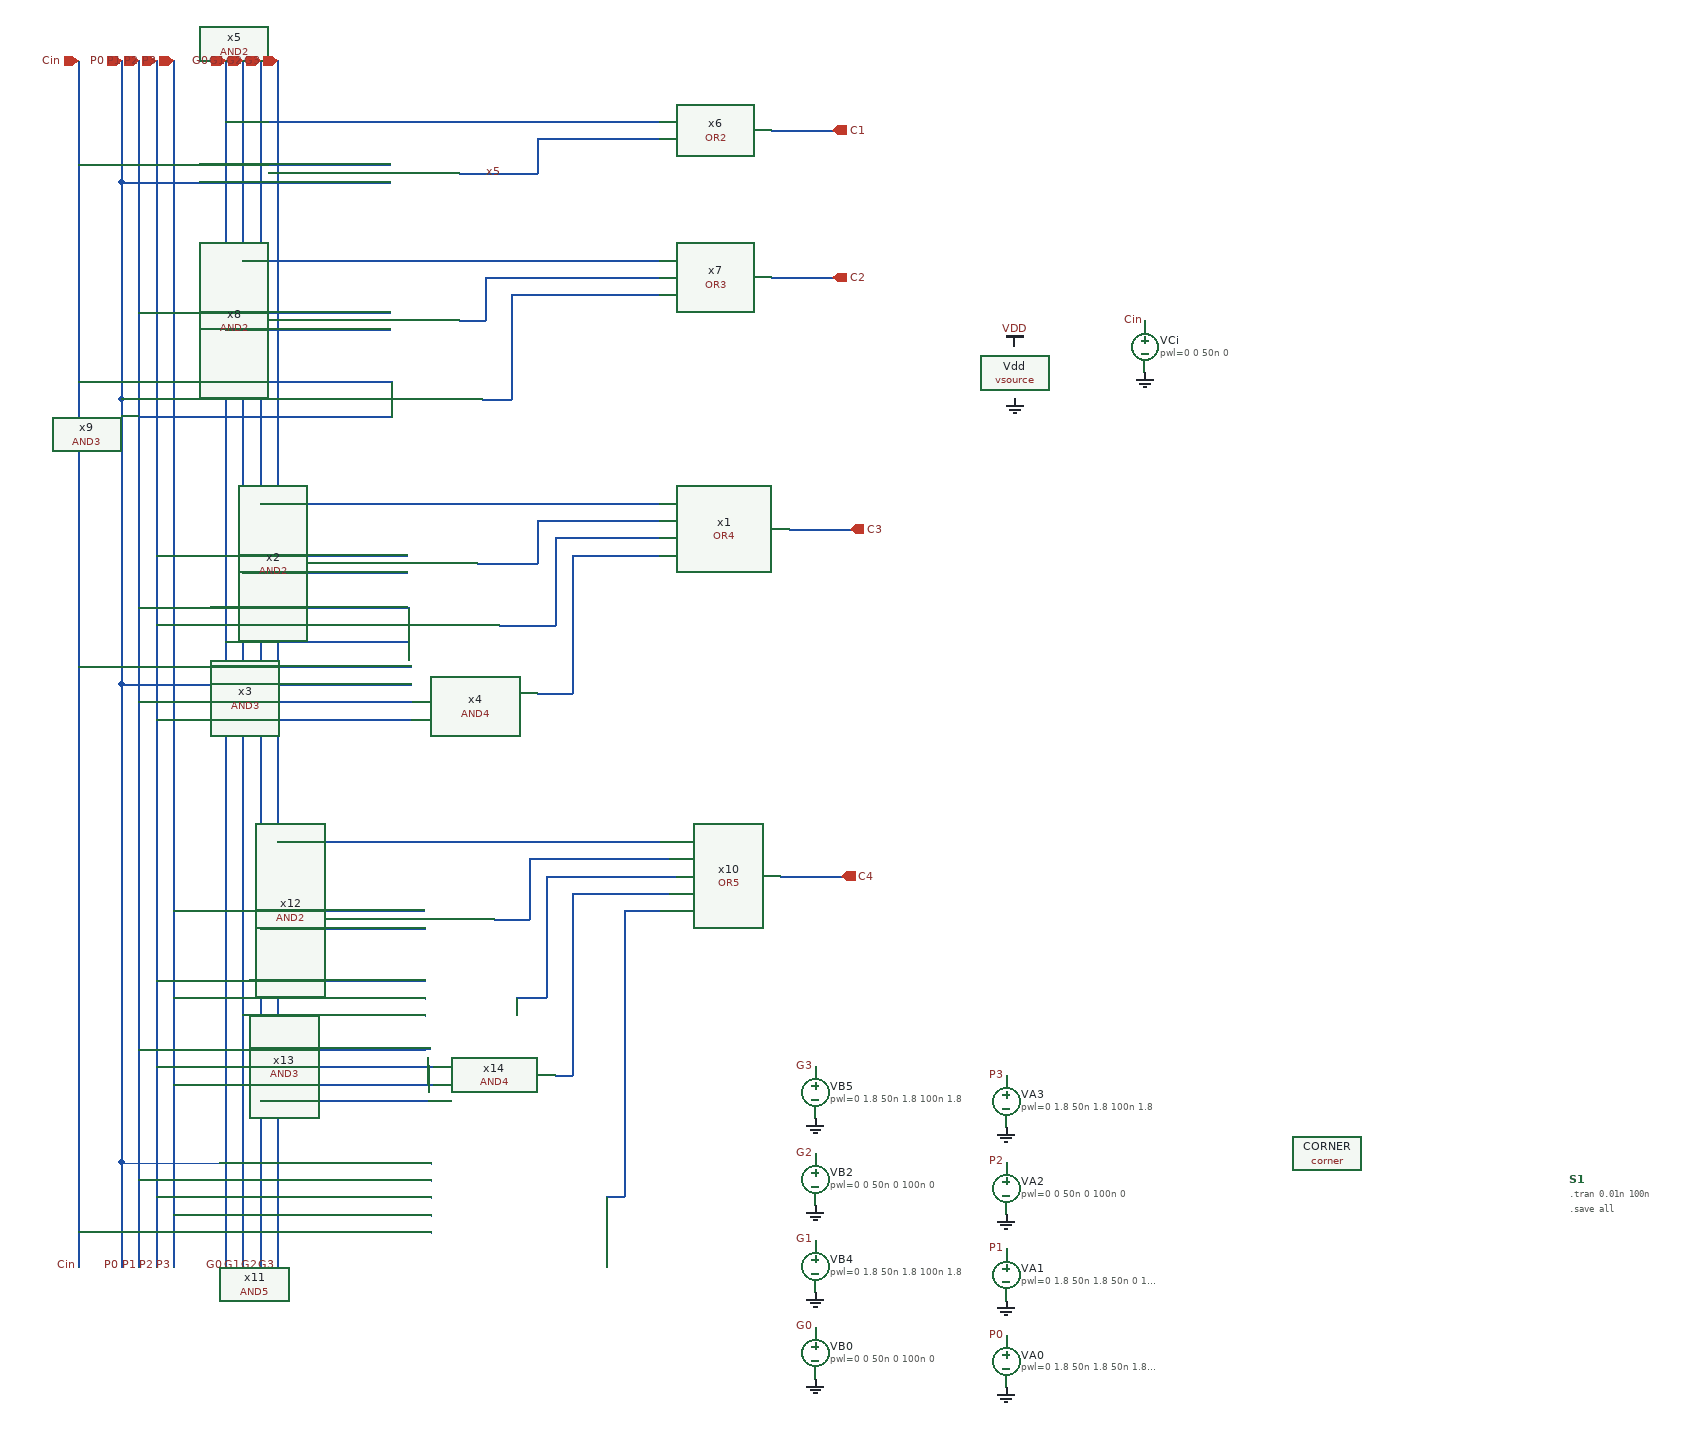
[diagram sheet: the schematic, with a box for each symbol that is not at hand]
v {xschem version=3.4.5 file_version=1.2
}
G {}
K {}
V {}
S {}
E {}
B 2 2080 -1280 2880 -880 {flags=graph
y1=0
y2=2
ypos1=-0.31094502
ypos2=1.6890548
divy=5
subdivy=1
unity=1
x1=0
x2=10e-8
divx=5
subdivx=1
xlabmag=1.0
ylabmag=1.0


dataset=-1
unitx=1
logx=0
logy=0
digital=1

color="8 8 11 6"
node="p;p3,p2,p1,p0
g;g3,g2,g1,g0
c;c4,c3,c2,c1
x5"}
N 1300 -1760 1610 -1760 {
lab=G0}
N 1050 -1710 1340 -1710 {
lab=Cin}
N 1100 -1690 1340 -1690 {
lab=P0}
N 1490 -1700 1500 -1700 {
lab=x5}
N 1580 -1740 1610 -1740 {
lab=x5}
N 1340 -1690 1410 -1690 {
lab=P0}
N 1340 -1710 1410 -1710 {
lab=Cin}
N 1320 -1600 1610 -1600 {
lab=G1}
N 1220 -1760 1300 -1760 {
lab=G0}
N 1500 -1700 1580 -1700 {
lab=x5}
N 1580 -1740 1580 -1700 {
lab=x5}
N 1240 -1600 1320 -1600 {
lab=G1}
N 1120 -1540 1410 -1540 {
lab=P1}
N 1220 -1520 1410 -1520 {
lab=G0}
N 1120 -1420 1410 -1420 {
lab=P1}
N 1100 -1440 1410 -1440 {
lab=P0}
N 1050 -1460 1410 -1460 {
lab=Cin}
N 1490 -1530 1520 -1530 {
lab=#net1}
N 1520 -1580 1520 -1530 {
lab=#net1}
N 1520 -1580 1610 -1580 {
lab=#net1}
N 1550 -1560 1550 -1440 {
lab=#net2}
N 1550 -1560 1610 -1560 {
lab=#net2}
N 1260 -1320 1610 -1320 {
lab=G2}
N 1610 -1760 1720 -1760 {
lab=G0}
N 1610 -1740 1720 -1740 {
lab=x5}
N 1610 -1600 1720 -1600 {
lab=G1}
N 1610 -1580 1720 -1580 {
lab=#net1}
N 1610 -1560 1720 -1560 {
lab=#net2}
N 1610 -1320 1720 -1320 {
lab=G2}
N 1050 -1131 1435 -1131 {
lab=Cin}
N 1101 -1111 1435 -1111 {
lab=P0}
N 1100 -1111 1101 -1111 {
lab=P0}
N 1120 -1091 1436 -1091 {
lab=P1}
N 1140 -1071 1435 -1071 {
lab=P2}
N 1220 -1160 1430 -1160 {
lab=G0}
N 1240 -1240 1430 -1240 {
lab=G1}
N 1120 -1200 1430 -1200 {
lab=P1}
N 1140 -1180 1430 -1180 {
lab=P2}
N 1140 -1260 1430 -1260 {
lab=P2}
N 1510 -1250 1580 -1250 {
lab=#net3}
N 1580 -1300 1580 -1250 {
lab=#net3}
N 1580 -1300 1720 -1300 {
lab=#net3}
N 1600 -1280 1600 -1180 {
lab=#net4}
N 1600 -1280 1720 -1280 {
lab=#net4}
N 1580 -1100 1620 -1100 {
lab=#net5}
N 1620 -1260 1620 -1100 {
lab=#net5}
N 1620 -1260 1720 -1260 {
lab=#net5}
N 1260 -830 1450 -830 {
lab=G2}
N 1160 -850 1449 -850 {
lab=P3}
N 1140 -770 1451 -769 {
lab=P2}
N 1160 -750 1451 -749 {
lab=P3}
N 1240 -730 1451 -729 {
lab=G1}
N 1160 -500 1457 -499 {
lab=P3}
N 1140 -520 1457 -519 {
lab=P2}
N 1120 -540 1457 -539 {
lab=P1}
N 1100 -560 1457 -559 {
lab=P0}
N 1050 -480 1457 -479 {
lab=Cin}
N 1530 -840 1570 -840 {
lab=#net6}
N 1570 -910 1570 -840 {
lab=#net6}
N 1570 -910 1730 -910 {
lab=#net6}
N 1560 -750 1590 -750 {
lab=#net7}
N 1590 -890 1590 -750 {
lab=#net7}
N 1590 -890 1740 -890 {
lab=#net7}
N 1600 -660 1620 -660 {
lab=#net8}
N 1620 -870 1620 -660 {
lab=#net8}
N 1620 -870 1730 -870 {
lab=#net8}
N 1660 -520 1680 -520 {
lab=#net9}
N 1680 -850 1680 -520 {
lab=#net9}
N 1850 -1750 1920 -1750 {
lab=C1}
N 1850 -1580 1920 -1580 {
lab=C2}
N 1870 -1290 1940 -1290 {
lab=C3}
N 1860 -890 1930 -890 {
lab=C4}
N 1280 -930 1722 -930 {
lab=G3}
N 1680 -850 1722 -850 {
lab=#net9}
N 1730 -870 1732 -870 {
lab=#net8}
N 1730 -910 1732 -910 {
lab=#net6}
N 1411 -1420 1411 -1419 {
lab=P1}
N 1410 -1420 1411 -1420 {
lab=P1}
N 1411 -1440 1411 -1439 {
lab=P0}
N 1410 -1440 1411 -1440 {
lab=P0}
N 1411 -1460 1411 -1459 {
lab=Cin}
N 1410 -1460 1411 -1460 {
lab=Cin}
N 1431 -1160 1431 -1159 {
lab=G0}
N 1430 -1160 1431 -1160 {
lab=G0}
N 1431 -1180 1431 -1179 {
lab=P2}
N 1430 -1180 1431 -1180 {
lab=P2}
N 1431 -1200 1431 -1199 {
lab=P1}
N 1429 -1200 1431 -1200 {
lab=P1}
N 1050 -1829 1050 -439 {
lab=Cin}
N 1120 -1830 1120 -440 {
lab=P1}
N 1140 -1830 1140 -440 {
lab=P2}
N 1160 -1830 1160 -440 {
lab=P3}
N 1220 -1830 1220 -440 {
lab=G0}
N 1240 -1830 1240 -440 {
lab=G1}
N 1260 -1830 1260 -440 {
lab=G2}
N 1280 -1830 1280 -440 {
lab=G3}
N 1240 -440 1240 -439 {
lab=G1}
N 1280 -440 1280 -439 {
lab=G3}
N 1260 -440 1260 -439 {
lab=G2}
N 1220 -440 1220 -439 {
lab=G0}
N 1160 -440 1160 -439 {
lab=P3}
N 1140 -440 1140 -439 {
lab=P2}
N 1120 -440 1120 -439 {
lab=P1}
N 1100 -440 1100 -439 {
lab=P0}
N 1100 -1830 1100 -1690 {
lab=P0}
N 1100 -1690 1100 -1440 {
lab=P0}
N 1100 -1440 1100 -1111 {
lab=P0}
N 1100 -1111 1100 -560 {
lab=P0}
N 1100 -560 1100 -439 {
lab=P0}
N 1516 -1439 1550 -1439 {
lab=#net2}
N 1550 -1440 1550 -1439 {
lab=#net2}
N 1536 -1179 1600 -1179 {
lab=#net4}
N 1600 -1180 1600 -1179 {
lab=#net4}
N 1556 -750 1556 -749 {
lab=#net7}
N 1556 -750 1560 -750 {
lab=#net7}
N 1659 -520 1659 -519 {
lab=#net9}
N 1659 -520 1660 -520 {
lab=#net9}
N 1120 -690 1450 -690 {
lab=P1}
N 1140 -670 1460 -670 {
lab=P2}
N 1160 -650 1460 -650 {
lab=P3}
N 1450 -691 1456 -691 {
lab=P1}
N 1450 -691 1450 -690 {
lab=P1}
N 1454 -671 1454 -670 {
lab=P2}
N 1454 -651 1454 -650 {
lab=P3}
N 1260 -631 1454 -631 {
lab=G2}
C {AND2.sym} 1450 -1700 0 0 {name=x5}
C {OR2.sym} 1770 -1750 0 0 {name=x6}
C {OR3.sym} 1790 -1580 0 0 {name=x7}
C {AND2.sym} 1450 -1530 0 0 {name=x8}
C {AND3.sym} 1460 -1440 0 0 {name=x9}
C {devices/ipin.sym} 1100 -1830 1 0 {name=p1 sig_type=std_logic lab=P0}
C {devices/ipin.sym} 1120 -1830 1 0 {name=p2 sig_type=std_logic lab=P1}
C {devices/ipin.sym} 1140 -1830 1 0 {name=p3 sig_type=std_logic lab=P2}
C {devices/ipin.sym} 1160 -1830 1 0 {name=p4 sig_type=std_logic lab=P3}
C {devices/ipin.sym} 1220 -1830 1 0 {name=p5 sig_type=std_logic lab=G0}
C {devices/ipin.sym} 1240 -1830 1 0 {name=p6 sig_type=std_logic lab=G1}
C {devices/ipin.sym} 1260 -1830 1 0 {name=p7 sig_type=std_logic lab=G2}
C {devices/ipin.sym} 1280 -1830 1 0 {name=p8 sig_type=std_logic lab=G3}
C {devices/ipin.sym} 1050 -1830 1 0 {name=p9 sig_type=std_logic lab=Cin}
C {OR4.sym} 1870 -1290 0 0 {name=x1}
C {AND2.sym} 1470 -1250 0 0 {name=x2}
C {AND3.sym} 1480 -1180 0 0 {name=x3}
C {AND4.sym} 1520 -1100 0 0 {name=x4}
C {OR5.sym} 1790 -890 0 0 {name=x10}
C {AND2.sym} 1490 -840 0 0 {name=x12}
C {AND3.sym} 1500 -750 0 0 {name=x13}
C {AND4.sym} 1540 -660 0 0 {name=x14}
C {devices/lab_pin.sym} 1100 -440 1 1 {name=p10 sig_type=std_logic lab=P0}
C {devices/lab_pin.sym} 1120 -440 1 1 {name=p11 sig_type=std_logic lab=P1}
C {devices/lab_pin.sym} 1140 -440 1 1 {name=p12 sig_type=std_logic lab=P2}
C {devices/lab_pin.sym} 1160 -440 1 1 {name=p13 sig_type=std_logic lab=P3}
C {devices/lab_pin.sym} 1220 -440 1 1 {name=p14 sig_type=std_logic lab=G0}
C {devices/lab_pin.sym} 1240 -440 1 1 {name=p15 sig_type=std_logic lab=G1}
C {devices/lab_pin.sym} 1260 -440 1 1 {name=p16 sig_type=std_logic lab=G2}
C {devices/lab_pin.sym} 1280 -440 1 1 {name=p17 sig_type=std_logic lab=G3}
C {devices/lab_pin.sym} 1050 -440 1 1 {name=p18 sig_type=std_logic lab=Cin}
C {devices/opin.sym} 1920 -1750 0 0 {name=p19 sig_type=std_logic lab=C1}
C {devices/opin.sym} 1920 -1580 0 0 {name=p20 sig_type=std_logic lab=C2}
C {devices/opin.sym} 1940 -1290 0 0 {name=p21 sig_type=std_logic lab=C3}
C {devices/opin.sym} 1930 -890 0 0 {name=p22 sig_type=std_logic lab=C4}
C {AND5.sym} 1550 -520 0 0 {name=x11}
C {devices/vsource.sym} 2120 -630 0 0 {name=VA3 value="pwl=0 1.8 50n 1.8 100n 1.8" savecurrent=false}
C {devices/lab_pin.sym} 2120 -660 0 0 {name=p23 sig_type=std_logic lab=P3}
C {devices/vsource.sym} 2120 -530 0 0 {name=VA2 value="pwl=0 0 50n 0 100n 0" savecurrent=false}
C {devices/lab_pin.sym} 2120 -560 0 0 {name=p24 sig_type=std_logic lab=P2}
C {devices/vsource.sym} 2120 -430 0 0 {name=VA1 value="pwl=0 1.8 50n 1.8 50n 0 100n 0" savecurrent=false}
C {devices/lab_pin.sym} 2120 -460 0 0 {name=p25 sig_type=std_logic lab=P1}
C {devices/vsource.sym} 2120 -330 0 0 {name=VA0 value="pwl=0 1.8 50n 1.8 50n 1.8 100n 1.8" savecurrent=false}
C {devices/lab_pin.sym} 2120 -360 0 0 {name=VA4 sig_type=std_logic lab=P0}
C {devices/vsource.sym} 1900 -640 0 0 {name=VB5 value="pwl=0 1.8 50n 1.8 100n 1.8" savecurrent=false}
C {devices/lab_pin.sym} 1900 -670 0 0 {name=VB1 sig_type=std_logic lab=G3}
C {devices/vsource.sym} 1900 -540 0 0 {name=VB2 value="pwl=0 0 50n 0 100n 0" savecurrent=false}
C {devices/lab_pin.sym} 1900 -570 0 0 {name=VB3 sig_type=std_logic lab=G2}
C {devices/vsource.sym} 1900 -440 0 0 {name=VB4 value="pwl=0 1.8 50n 1.8 100n 1.8" savecurrent=false}
C {devices/lab_pin.sym} 1900 -470 0 0 {name=VB6 sig_type=std_logic lab=G1}
C {devices/vsource.sym} 1900 -340 0 0 {name=VB0 value="pwl=0 0 50n 0 100n 0" savecurrent=false}
C {devices/lab_pin.sym} 1900 -370 0 0 {name=VB8 sig_type=std_logic lab=G0}
C {devices/gnd.sym} 2120 -300 0 0 {name=l13 lab=GND}
C {devices/gnd.sym} 1900 -310 0 0 {name=l14 lab=GND}
C {devices/gnd.sym} 2120 -400 0 0 {name=l15 lab=GND}
C {devices/gnd.sym} 1900 -410 0 0 {name=l16 lab=GND}
C {devices/gnd.sym} 2120 -500 0 0 {name=l17 lab=GND}
C {devices/gnd.sym} 1900 -510 0 0 {name=l18 lab=GND}
C {devices/gnd.sym} 1900 -610 0 0 {name=l19 lab=GND}
C {devices/gnd.sym} 2120 -600 0 0 {name=l20 lab=GND}
C {sky130_fd_pr/corner.sym} 2490 -570 0 0 {name=CORNER only_toplevel=true corner=tt}
C {devices/code_shown.sym} 2770 -540 0 0 {name=S1 only_toplevel=false value=".tran 0.01n 100n
.save all"}
C {devices/vsource.sym} 2280 -1500 0 0 {name=VCi value="pwl=0 0 50n 0 " savecurrent=false}
C {devices/lab_pin.sym} 2280 -1530 0 0 {name=Ci1 sig_type=std_logic lab=Cin}
C {devices/gnd.sym} 2280 -1470 0 0 {name=Ci2 lab=GND}
C {devices/lab_pin.sym} 1540 -1700 0 0 {name=Ci3 sig_type=std_logic lab=x5}
C {devices/vsource.sym} 2130 -1470 0 0 {name=Vdd value=1.8 savecurrent=false}
C {devices/vdd.sym} 2130 -1500 0 0 {name=l11 lab=VDD}
C {devices/gnd.sym} 2130 -1440 0 0 {name=l1 lab=GND}
